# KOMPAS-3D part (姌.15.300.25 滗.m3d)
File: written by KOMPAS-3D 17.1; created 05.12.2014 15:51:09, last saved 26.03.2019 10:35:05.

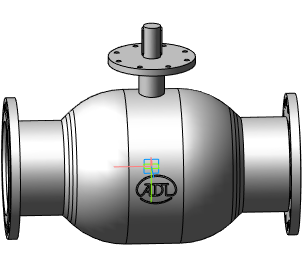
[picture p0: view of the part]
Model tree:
1. Операция без истории:4  (labels: Сталь 20  ГОСТ 1050-88)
